VERSION 5.8 ;
BUSBITCHARS "[]" ;
DIVIDERCHAR "/" ;
UNITS
    DATABASE MICRONS 1000 ;
END UNITS

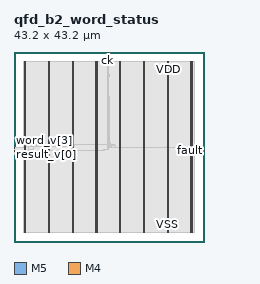
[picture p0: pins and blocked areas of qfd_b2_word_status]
MACRO qfd_b2_word_status
  FOREIGN qfd_b2_word_status 0 0 ;
  CLASS BLOCK ;
  SIZE 43.2 BY 43.2 ;
  PIN ck
    DIRECTION INPUT ;
    USE SIGNAL ;
    PORT
      LAYER M5 ;
        RECT  21.36 43.116 21.384 43.2 ;
    END
  END ck
  PIN fault
    DIRECTION OUTPUT ;
    USE SIGNAL ;
    PORT
      LAYER M4 ;
        RECT  43.116 20.688 43.2 20.712 ;
    END
  END fault
  PIN result_v[0]
    DIRECTION INPUT ;
    USE SIGNAL ;
    PORT
      LAYER M4 ;
        RECT  0 19.824 0.084 19.848 ;
    END
  END result_v[0]
  PIN result_v[1]
    DIRECTION INPUT ;
    USE SIGNAL ;
    PORT
      LAYER M4 ;
        RECT  0 19.92 0.084 19.944 ;
    END
  END result_v[1]
  PIN result_v[2]
    DIRECTION INPUT ;
    USE SIGNAL ;
    PORT
      LAYER M4 ;
        RECT  0 20.016 0.084 20.04 ;
    END
  END result_v[2]
  PIN result_v[3]
    DIRECTION INPUT ;
    USE SIGNAL ;
    PORT
      LAYER M4 ;
        RECT  0 20.112 0.084 20.136 ;
    END
  END result_v[3]
  PIN result_v[4]
    DIRECTION INPUT ;
    USE SIGNAL ;
    PORT
      LAYER M4 ;
        RECT  0 20.208 0.084 20.232 ;
    END
  END result_v[4]
  PIN result_v[5]
    DIRECTION INPUT ;
    USE SIGNAL ;
    PORT
      LAYER M4 ;
        RECT  0 20.304 0.084 20.328 ;
    END
  END result_v[5]
  PIN rst_n
    DIRECTION INPUT ;
    USE SIGNAL ;
    PORT
      LAYER M5 ;
        RECT  21.456 43.116 21.48 43.2 ;
    END
  END rst_n
  PIN word_fault[0]
    DIRECTION INPUT ;
    USE SIGNAL ;
    PORT
      LAYER M4 ;
        RECT  0 20.4 0.084 20.424 ;
    END
  END word_fault[0]
  PIN word_fault[1]
    DIRECTION INPUT ;
    USE SIGNAL ;
    PORT
      LAYER M4 ;
        RECT  0 20.496 0.084 20.52 ;
    END
  END word_fault[1]
  PIN word_fault[2]
    DIRECTION INPUT ;
    USE SIGNAL ;
    PORT
      LAYER M4 ;
        RECT  0 20.592 0.084 20.616 ;
    END
  END word_fault[2]
  PIN word_fault[3]
    DIRECTION INPUT ;
    USE SIGNAL ;
    PORT
      LAYER M4 ;
        RECT  0 20.688 0.084 20.712 ;
    END
  END word_fault[3]
  PIN word_fault[4]
    DIRECTION INPUT ;
    USE SIGNAL ;
    PORT
      LAYER M4 ;
        RECT  0 20.784 0.084 20.808 ;
    END
  END word_fault[4]
  PIN word_fault[5]
    DIRECTION INPUT ;
    USE SIGNAL ;
    PORT
      LAYER M4 ;
        RECT  0 20.88 0.084 20.904 ;
    END
  END word_fault[5]
  PIN word_v[0]
    DIRECTION INPUT ;
    USE SIGNAL ;
    PORT
      LAYER M4 ;
        RECT  0 20.976 0.084 21 ;
    END
  END word_v[0]
  PIN word_v[1]
    DIRECTION INPUT ;
    USE SIGNAL ;
    PORT
      LAYER M4 ;
        RECT  0 21.072 0.084 21.096 ;
    END
  END word_v[1]
  PIN word_v[2]
    DIRECTION INPUT ;
    USE SIGNAL ;
    PORT
      LAYER M4 ;
        RECT  0 21.168 0.084 21.192 ;
    END
  END word_v[2]
  PIN word_v[3]
    DIRECTION INPUT ;
    USE SIGNAL ;
    PORT
      LAYER M4 ;
        RECT  0 21.264 0.084 21.288 ;
    END
  END word_v[3]
  PIN word_v[4]
    DIRECTION INPUT ;
    USE SIGNAL ;
    PORT
      LAYER M4 ;
        RECT  0 21.36 0.084 21.384 ;
    END
  END word_v[4]
  PIN word_v[5]
    DIRECTION INPUT ;
    USE SIGNAL ;
    PORT
      LAYER M4 ;
        RECT  0 21.456 0.084 21.48 ;
    END
  END word_v[5]
  PIN VDD
    DIRECTION INOUT ;
    USE POWER ;
    PORT
      LAYER M5 ;
        RECT  40.392 2.151 40.512 41.049 ;
        RECT  34.992 2.151 35.112 41.049 ;
        RECT  29.592 2.151 29.712 41.049 ;
        RECT  24.192 2.151 24.312 41.049 ;
        RECT  18.792 2.151 18.912 41.049 ;
        RECT  13.392 2.151 13.512 41.049 ;
        RECT  7.992 2.151 8.112 41.049 ;
        RECT  2.592 2.151 2.712 41.049 ;
    END
  END VDD
  PIN VSS
    DIRECTION INOUT ;
    USE GROUND ;
    PORT
      LAYER M5 ;
        RECT  40.2 2.137 40.32 41.063 ;
        RECT  34.8 2.137 34.92 41.063 ;
        RECT  29.4 2.137 29.52 41.063 ;
        RECT  24 2.137 24.12 41.063 ;
        RECT  18.6 2.137 18.72 41.063 ;
        RECT  13.2 2.137 13.32 41.063 ;
        RECT  7.8 2.137 7.92 41.063 ;
        RECT  2.4 2.137 2.52 41.063 ;
    END
  END VSS
  OBS
    LAYER RVTN ;
     RECT  2.16 2.16 41.04 2.295 ;
     RECT  2.16 2.565 41.04 2.835 ;
     RECT  2.16 3.105 41.04 3.375 ;
     RECT  2.16 3.645 41.04 3.915 ;
     RECT  2.16 4.185 41.04 4.455 ;
     RECT  2.16 4.725 41.04 4.995 ;
     RECT  2.16 5.265 41.04 5.535 ;
     RECT  2.16 5.805 41.04 6.075 ;
     RECT  2.16 6.345 41.04 6.615 ;
     RECT  2.16 6.885 41.04 7.155 ;
     RECT  2.16 7.425 41.04 7.695 ;
     RECT  2.16 7.965 41.04 8.235 ;
     RECT  2.16 8.505 41.04 8.775 ;
     RECT  2.16 9.045 41.04 9.315 ;
     RECT  2.16 9.585 41.04 9.855 ;
     RECT  2.16 10.125 41.04 10.395 ;
     RECT  2.16 10.665 41.04 10.935 ;
     RECT  2.16 11.205 41.04 11.475 ;
     RECT  2.16 11.745 41.04 12.015 ;
     RECT  2.16 12.285 41.04 12.555 ;
     RECT  2.16 12.825 41.04 13.095 ;
     RECT  2.16 13.365 41.04 13.635 ;
     RECT  2.16 13.905 41.04 14.175 ;
     RECT  2.16 14.445 41.04 14.715 ;
     RECT  2.16 14.985 41.04 15.255 ;
     RECT  2.16 15.525 41.04 15.795 ;
     RECT  2.16 16.065 41.04 16.335 ;
     RECT  2.16 16.605 41.04 16.875 ;
     RECT  2.16 17.145 41.04 17.415 ;
     RECT  2.16 17.685 41.04 17.955 ;
     RECT  2.16 18.225 41.04 18.495 ;
     RECT  2.16 18.765 41.04 19.035 ;
     RECT  2.16 19.305 41.04 19.575 ;
     RECT  2.16 19.845 41.04 20.115 ;
     RECT  2.16 20.385 41.04 20.655 ;
     RECT  2.16 20.925 41.04 21.195 ;
     RECT  2.16 21.465 41.04 21.735 ;
     RECT  2.16 22.005 41.04 22.275 ;
     RECT  2.16 22.545 41.04 22.815 ;
     RECT  2.16 23.085 41.04 23.355 ;
     RECT  2.16 23.625 41.04 23.895 ;
     RECT  2.16 24.165 41.04 24.435 ;
     RECT  2.16 24.705 41.04 24.975 ;
     RECT  2.16 25.245 41.04 25.515 ;
     RECT  2.16 25.785 41.04 26.055 ;
     RECT  2.16 26.325 41.04 26.595 ;
     RECT  2.16 26.865 41.04 27.135 ;
     RECT  2.16 27.405 41.04 27.675 ;
     RECT  2.16 27.945 41.04 28.215 ;
     RECT  2.16 28.485 41.04 28.755 ;
     RECT  2.16 29.025 41.04 29.295 ;
     RECT  2.16 29.565 41.04 29.835 ;
     RECT  2.16 30.105 41.04 30.375 ;
     RECT  2.16 30.645 41.04 30.915 ;
     RECT  2.16 31.185 41.04 31.455 ;
     RECT  2.16 31.725 41.04 31.995 ;
     RECT  2.16 32.265 41.04 32.535 ;
     RECT  2.16 32.805 41.04 33.075 ;
     RECT  2.16 33.345 41.04 33.615 ;
     RECT  2.16 33.885 41.04 34.155 ;
     RECT  2.16 34.425 41.04 34.695 ;
     RECT  2.16 34.965 41.04 35.235 ;
     RECT  2.16 35.505 41.04 35.775 ;
     RECT  2.16 36.045 41.04 36.315 ;
     RECT  2.16 36.585 41.04 36.855 ;
     RECT  2.16 37.125 41.04 37.395 ;
     RECT  2.16 37.665 41.04 37.935 ;
     RECT  2.16 38.205 41.04 38.475 ;
     RECT  2.16 38.745 41.04 39.015 ;
     RECT  2.16 39.285 41.04 39.555 ;
     RECT  2.16 39.825 41.04 40.095 ;
     RECT  2.16 40.365 41.04 40.635 ;
     RECT  2.16 40.905 41.04 41.04 ;
    LAYER RVTP ;
     RECT  2.16 2.295 41.04 2.565 ;
     RECT  2.16 2.835 41.04 3.105 ;
     RECT  2.16 3.375 41.04 3.645 ;
     RECT  2.16 3.915 41.04 4.185 ;
     RECT  2.16 4.455 41.04 4.725 ;
     RECT  2.16 4.995 41.04 5.265 ;
     RECT  2.16 5.535 41.04 5.805 ;
     RECT  2.16 6.075 41.04 6.345 ;
     RECT  2.16 6.615 41.04 6.885 ;
     RECT  2.16 7.155 41.04 7.425 ;
     RECT  2.16 7.695 41.04 7.965 ;
     RECT  2.16 8.235 41.04 8.505 ;
     RECT  2.16 8.775 41.04 9.045 ;
     RECT  2.16 9.315 41.04 9.585 ;
     RECT  2.16 9.855 41.04 10.125 ;
     RECT  2.16 10.395 41.04 10.665 ;
     RECT  2.16 10.935 41.04 11.205 ;
     RECT  2.16 11.475 41.04 11.745 ;
     RECT  2.16 12.015 41.04 12.285 ;
     RECT  2.16 12.555 41.04 12.825 ;
     RECT  2.16 13.095 41.04 13.365 ;
     RECT  2.16 13.635 41.04 13.905 ;
     RECT  2.16 14.175 41.04 14.445 ;
     RECT  2.16 14.715 41.04 14.985 ;
     RECT  2.16 15.255 41.04 15.525 ;
     RECT  2.16 15.795 41.04 16.065 ;
     RECT  2.16 16.335 41.04 16.605 ;
     RECT  2.16 16.875 41.04 17.145 ;
     RECT  2.16 17.415 41.04 17.685 ;
     RECT  2.16 17.955 41.04 18.225 ;
     RECT  2.16 18.495 41.04 18.765 ;
     RECT  2.16 19.035 41.04 19.305 ;
     RECT  2.16 19.575 41.04 19.845 ;
     RECT  2.16 20.115 41.04 20.385 ;
     RECT  2.16 20.655 41.04 20.925 ;
     RECT  2.16 21.195 41.04 21.465 ;
     RECT  2.16 21.735 41.04 22.005 ;
     RECT  2.16 22.275 41.04 22.545 ;
     RECT  2.16 22.815 41.04 23.085 ;
     RECT  2.16 23.355 41.04 23.625 ;
     RECT  2.16 23.895 41.04 24.165 ;
     RECT  2.16 24.435 41.04 24.705 ;
     RECT  2.16 24.975 41.04 25.245 ;
     RECT  2.16 25.515 41.04 25.785 ;
     RECT  2.16 26.055 41.04 26.325 ;
     RECT  2.16 26.595 41.04 26.865 ;
     RECT  2.16 27.135 41.04 27.405 ;
     RECT  2.16 27.675 41.04 27.945 ;
     RECT  2.16 28.215 41.04 28.485 ;
     RECT  2.16 28.755 41.04 29.025 ;
     RECT  2.16 29.295 41.04 29.565 ;
     RECT  2.16 29.835 41.04 30.105 ;
     RECT  2.16 30.375 41.04 30.645 ;
     RECT  2.16 30.915 41.04 31.185 ;
     RECT  2.16 31.455 41.04 31.725 ;
     RECT  2.16 31.995 41.04 32.265 ;
     RECT  2.16 32.535 41.04 32.805 ;
     RECT  2.16 33.075 41.04 33.345 ;
     RECT  2.16 33.615 41.04 33.885 ;
     RECT  2.16 34.155 41.04 34.425 ;
     RECT  2.16 34.695 41.04 34.965 ;
     RECT  2.16 35.235 41.04 35.505 ;
     RECT  2.16 35.775 41.04 36.045 ;
     RECT  2.16 36.315 41.04 36.585 ;
     RECT  2.16 36.855 41.04 37.125 ;
     RECT  2.16 37.395 41.04 37.665 ;
     RECT  2.16 37.935 41.04 38.205 ;
     RECT  2.16 38.475 41.04 38.745 ;
     RECT  2.16 39.015 41.04 39.285 ;
     RECT  2.16 39.555 41.04 39.825 ;
     RECT  2.16 40.095 41.04 40.365 ;
     RECT  2.16 40.635 41.04 40.905 ;
    LAYER M1 ;
     RECT  2.16 2.151 41.04 41.049 ;
    LAYER M2 ;
     RECT  2.16 2.151 41.04 41.049 ;
     RECT  41.04 20.826 42.179 20.844 ;
    LAYER M3 ;
     RECT  2.415 2.143 2.505 2.413 ;
     RECT  7.815 2.143 7.905 2.413 ;
     RECT  13.215 2.143 13.305 2.413 ;
     RECT  18.615 2.143 18.705 2.413 ;
     RECT  24.015 2.143 24.105 2.413 ;
     RECT  29.415 2.143 29.505 2.413 ;
     RECT  34.815 2.143 34.905 2.413 ;
     RECT  40.215 2.143 40.305 2.413 ;
     RECT  2.415 2.413 2.697 19.201 ;
     RECT  5.4 19.345 5.814 19.507 ;
     RECT  2.415 19.201 3.402 19.543 ;
     RECT  4.608 19.507 5.814 19.543 ;
     RECT  2.415 19.543 5.814 19.615 ;
     RECT  2.304 19.615 5.814 20.551 ;
     RECT  13.215 2.413 13.497 20.731 ;
     RECT  18.615 2.413 18.897 20.731 ;
     RECT  2.304 20.551 5.85 20.821 ;
     RECT  40.215 2.413 40.497 20.821 ;
     RECT  20.592 20.731 20.61 20.849 ;
     RECT  42.156 20.683 42.174 20.849 ;
     RECT  12.456 20.731 13.497 20.861 ;
     RECT  18.615 20.731 18.99 20.909 ;
     RECT  2.304 20.821 6.39 20.921 ;
     RECT  40.215 20.821 40.698 20.921 ;
     RECT  2.304 20.921 6.102 20.993 ;
     RECT  20.376 20.965 20.394 21.005 ;
     RECT  12.456 20.861 12.474 21.101 ;
     RECT  40.215 20.921 40.518 21.119 ;
     RECT  37.512 20.893 37.53 21.199 ;
     RECT  37.332 21.199 37.998 21.235 ;
     RECT  37.332 21.235 38.394 21.271 ;
     RECT  40.215 21.119 40.497 21.271 ;
     RECT  37.332 21.271 38.97 21.389 ;
     RECT  39.888 21.271 40.497 21.389 ;
     RECT  37.332 21.389 38.646 21.437 ;
     RECT  34.815 2.413 35.097 21.541 ;
     RECT  37.908 21.437 38.646 21.569 ;
     RECT  34.776 21.541 35.097 21.659 ;
     RECT  38.628 21.569 38.646 21.659 ;
     RECT  2.304 20.993 6.066 21.811 ;
     RECT  21.42 21.403 21.438 21.811 ;
     RECT  13.215 20.861 13.497 21.901 ;
     RECT  23.112 21.811 23.13 21.929 ;
     RECT  2.304 21.811 6.246 22.037 ;
     RECT  21.42 21.811 22.23 22.045 ;
     RECT  2.304 22.037 4.05 22.109 ;
     RECT  5.004 22.037 6.246 22.199 ;
     RECT  21.42 22.045 22.95 22.199 ;
     RECT  21.42 22.199 22.698 22.205 ;
     RECT  13.215 21.901 13.698 22.222 ;
     RECT  2.304 22.109 3.294 22.235 ;
     RECT  5.94 22.199 6.246 22.235 ;
     RECT  21.744 22.205 22.698 22.235 ;
     RECT  5.004 22.199 5.202 22.307 ;
     RECT  5.94 22.235 5.994 22.307 ;
     RECT  5.184 22.307 5.202 22.343 ;
     RECT  5.94 22.307 5.958 22.343 ;
     RECT  4.032 22.109 4.05 22.469 ;
     RECT  21.744 22.235 22.05 22.469 ;
     RECT  2.304 22.235 3.186 22.505 ;
     RECT  2.415 22.505 2.754 22.541 ;
     RECT  21.744 22.469 21.906 22.541 ;
     RECT  21.744 22.541 21.762 27.869 ;
     RECT  21.636 27.877 21.654 32.999 ;
     RECT  21.528 33.007 21.546 37.633 ;
     RECT  21.528 37.633 21.654 38.129 ;
     RECT  21.528 38.129 21.546 38.189 ;
     RECT  2.415 22.541 2.697 40.787 ;
     RECT  7.815 2.413 8.097 40.787 ;
     RECT  13.215 22.222 13.497 40.787 ;
     RECT  18.615 20.909 18.897 40.787 ;
     RECT  24.015 2.413 24.297 40.787 ;
     RECT  29.415 2.413 29.697 40.787 ;
     RECT  34.815 21.659 35.097 40.787 ;
     RECT  40.215 21.389 40.497 40.787 ;
     RECT  2.415 40.787 2.505 41.057 ;
     RECT  7.815 40.787 7.905 41.057 ;
     RECT  13.215 40.787 13.305 41.057 ;
     RECT  18.615 40.787 18.705 41.057 ;
     RECT  24.015 40.787 24.105 41.057 ;
     RECT  29.415 40.787 29.505 41.057 ;
     RECT  34.815 40.787 34.905 41.057 ;
     RECT  40.215 40.787 40.305 41.057 ;
    LAYER M4 ;
     RECT  0.06 19.824 2.408 21.48 ;
     RECT  2.408 2.148 2.512 41.052 ;
     RECT  2.512 2.418 2.704 40.782 ;
     RECT  2.704 20.4 3.197 21.72 ;
     RECT  3.197 20.4 3.341 20.424 ;
     RECT  3.197 21.696 4.525 21.72 ;
     RECT  4.525 20.832 7.808 21.72 ;
     RECT  7.808 2.148 7.912 41.052 ;
     RECT  7.912 2.418 8.104 40.782 ;
     RECT  8.104 20.832 13.093 21.72 ;
     RECT  13.093 20.832 13.208 22.056 ;
     RECT  13.208 2.148 13.312 41.052 ;
     RECT  13.312 2.418 13.504 40.782 ;
     RECT  13.504 20.88 18.608 20.904 ;
     RECT  13.504 22.176 18.608 22.2 ;
     RECT  18.608 2.148 18.712 41.052 ;
     RECT  18.712 2.418 18.904 40.782 ;
     RECT  18.904 20.736 19.001 20.904 ;
     RECT  19.001 20.736 20.365 20.76 ;
     RECT  20.365 20.736 20.621 21 ;
     RECT  20.621 20.976 21.395 21 ;
     RECT  18.904 22.176 21.409 22.2 ;
     RECT  21.409 21.408 21.449 22.2 ;
     RECT  21.445 43.056 21.587 43.08 ;
     RECT  21.517 38.16 21.601 38.184 ;
     RECT  21.449 21.408 24.008 21.432 ;
     RECT  24.008 2.148 24.112 41.052 ;
     RECT  24.112 2.418 24.304 40.782 ;
     RECT  24.304 21.408 29.408 21.432 ;
     RECT  29.408 2.148 29.512 41.052 ;
     RECT  29.512 2.418 29.704 40.782 ;
     RECT  29.704 21.408 34.808 21.432 ;
     RECT  34.808 2.148 34.912 41.052 ;
     RECT  34.912 2.418 35.104 40.782 ;
     RECT  35.104 21.408 37.361 21.432 ;
     RECT  40.208 2.148 40.312 41.052 ;
     RECT  40.312 2.418 40.504 40.782 ;
     RECT  42.145 20.688 43.164 20.712 ;
    LAYER M5 ;
     RECT  2.4 2.137 2.52 2.151 ;
     RECT  7.8 2.137 7.92 2.151 ;
     RECT  13.2 2.137 13.32 2.151 ;
     RECT  18.6 2.137 18.72 2.151 ;
     RECT  24 2.137 24.12 2.151 ;
     RECT  29.4 2.137 29.52 2.151 ;
     RECT  34.8 2.137 34.92 2.151 ;
     RECT  40.2 2.137 40.32 2.151 ;
     RECT  13.2 2.151 13.512 20.869 ;
     RECT  13.104 20.869 13.512 22.067 ;
     RECT  21.36 20.965 21.384 38.149 ;
     RECT  2.4 2.151 2.712 41.049 ;
     RECT  7.8 2.151 8.112 41.049 ;
     RECT  13.2 22.067 13.512 41.049 ;
     RECT  18.6 2.151 18.912 41.049 ;
     RECT  24 2.151 24.312 41.049 ;
     RECT  29.4 2.151 29.712 41.049 ;
     RECT  34.8 2.151 35.112 41.049 ;
     RECT  40.2 2.151 40.512 41.049 ;
     RECT  2.4 41.049 2.52 41.063 ;
     RECT  7.8 41.049 7.92 41.063 ;
     RECT  13.2 41.049 13.32 41.063 ;
     RECT  18.6 41.049 18.72 41.063 ;
     RECT  24 41.049 24.12 41.063 ;
     RECT  29.4 41.049 29.52 41.063 ;
     RECT  34.8 41.049 34.92 41.063 ;
     RECT  40.2 41.049 40.32 41.063 ;
     RECT  21.36 38.149 21.576 43.091 ;
     RECT  21.36 43.091 21.48 43.152 ;
  END
END qfd_b2_word_status
END LIBRARY
